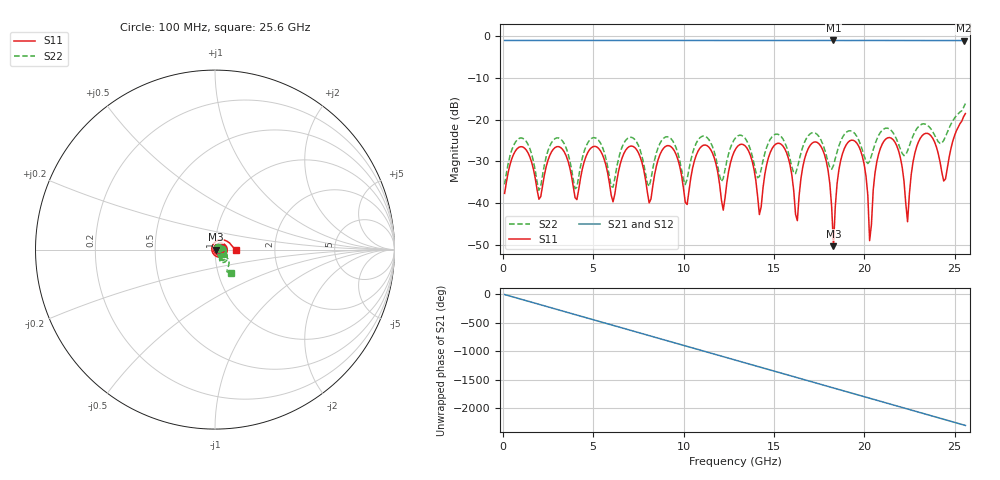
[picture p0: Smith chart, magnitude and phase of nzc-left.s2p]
! scikit-rf 1.8.0 golden reference; NZC forced split impedance 50 ohm
# Hz S RI R 50
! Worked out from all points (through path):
!   256 points, 100 MHz to 25.6 GHz, reference 50 ohm
!   highest |S21| = -1.00 dB at 18.3 GHz (marker M1); lowest = -1.1 dB at 25.5 GHz (marker M2)
!   group delay of S21, straight-line fit = 250 ps
!   lowest |S11| = -50.4 dB at 18.3 GHz (marker M3), VSWR 1.01, Z = 50.3 + j0.0105 ohm
!   |S11| at or under -10 dB: start of sweep to end of sweep
!   |S22| runs from -37.0 to -16.1 dB; largest |S21 - S12| = 0
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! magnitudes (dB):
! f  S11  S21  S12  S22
! 100 MHz  -37.7  -1.0  -1.0  -35.6
! 4.4 GHz  -31.9  -1.0  -1.0  -29.2
! 8.6 GHz  -29.6  -1.0  -1.0  -26.7
! 10.2 GHz  -40.4  -1.0  -1.0  -34.3
! 11.3 GHz  -26.2  -1.0  -1.0  -24.3
! 12.2 GHz  -41.7  -1.0  -1.0  -34.1
! 12.9 GHz  -26.9  -1.0  -1.0  -24.3
! 14.2 GHz  -42.8  -1.0  -1.0  -33.7
! 15.5 GHz  -26.3  -1.0  -1.0  -24.6
! 16.3 GHz  -44.3  -1.0  -1.0  -31.6
! 17.1 GHz  -25.7  -1.0  -1.0  -23.2
! 17.9 GHz  -30.0  -1.0  -1.0  -28.5
! 18.3 GHz  -50.4  -1.0  -1.0  -31.0
! 19 GHz  -26.1  -1.0  -1.0  -23.1
! 19.9 GHz  -28.9  -1.0  -1.0  -27.3
! 20.3 GHz  -49.1  -1.0  -1.0  -30.0
! 21.4 GHz  -24.3  -1.0  -1.0  -22.3
! 22.4 GHz  -44.5  -1.0  -1.0  -27.5
! 23.1 GHz  -24.5  -1.0  -1.0  -21.3
! 24.4 GHz  -34.7  -1.0  -1.0  -25.0
! 25.5 GHz  -19.3  -1.1  -1.1  -17.1
! 25.6 GHz  -18.6  -1.0  -1.0  -16.1
